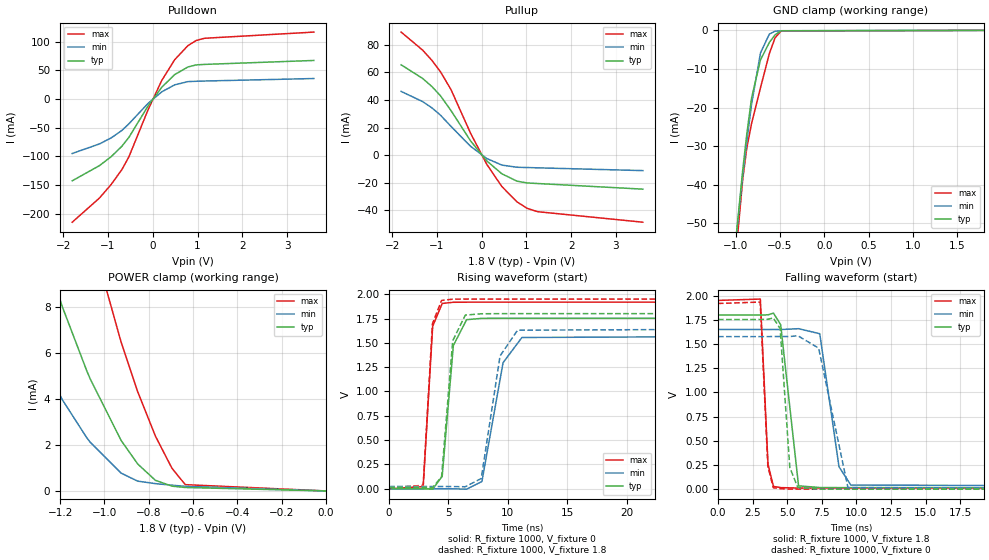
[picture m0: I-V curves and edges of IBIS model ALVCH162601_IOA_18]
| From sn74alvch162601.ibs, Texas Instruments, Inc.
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[Model]   ALVCH162601_IOA_18
Model_type  I/O
Vinl=0.5775
Vinh=1.2675
Enable   Active-Low
Vref =   0
Rref =   1000
Cref =   30p
Vmeas =   0.9
| variable   typ   min   max
C_comp   8.60pF   7.58pF   9.42pF
| C_pullup   9.70pF   8.14pF   10.52pF
| C_pulldown   13.30pF   10.04pF   17.23pF
| C_tri-state   8.60pF   7.58pF   9.42pF
[Temperature Range]   40   100   -40
| Ambient temperature   25   85   -40
[Voltage range]   1.8   1.65   1.95
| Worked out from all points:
|   slope of the pulldown table from 0 to 0.27 V, typ, clamps not added: 10.2 ohm
|   slope of the pullup table from 0 to 0.27 V, typ, clamps not added: 30.2 ohm
|   GND clamp passes 1 mA (typ) near -0.55 V on its own axis
|   POWER clamp passes 1 mA (typ) near -0.83 V on its own axis
|   rising waveform, R_fixture 1000, V_fixture 0: 20-80 % time 655ps typ, 1.3ns min, 392ps max; typ from 0 V to 1.75 V
|   falling waveform, R_fixture 1000, V_fixture 1.8: 20-80 % time 461ps typ, 839ps min, 271ps max; typ from 1.8 V to 0.016 V
|   rising waveform, R_fixture 1000, V_fixture 1.8: 20-80 % time 620ps typ, 1.14ns min, 383ps max; typ from 0.016 V to 1.8 V
|   falling waveform, R_fixture 1000, V_fixture 0: 20-80 % time 453ps typ, 852ps min, 267ps max; typ from 1.75 V to 0 V
[GND Clamp]
| ALVCH162601_IOA_18
|   Voltage   I(typ)   I(min)   I(max)
-1.8V     -267.7mA   -247.3mA   -300.9mA
-1.09V    -76.1mA    -74.2mA    -82.32mA
-1.075V   -72.37mA   -70.82mA   -78.1mA
-1.055V   -67.46mA   -66.36mA   -72.53mA
-920mV    -36.17mA   -37.65mA   -38.59mA
-875mV    -26.98mA   -28.88mA   -30.56mA
-820mV    -17.47mA   -19.08mA   -24.08mA
-720mV    -7.652mA   -5.864mA   -14.89mA
-620mV    -3.141mA   -959.9uA   -6.029mA
-555mV    -1.142mA   -210.2uA   -1.921mA
-485mV    -97.9uA    -108.2uA   -133.2uA
1.8V      63.53pA    9.524uA    -22.72uA
[POWER Clamp]
| ALVCH162601_IOA_18
|   Voltage   I(typ)   I(min)   I(max)
-1.8V     29.94mA    18.79mA    48.32mA
-1.545V   19.69mA    11.65mA    33.78mA
-1.31V    11.56mA    6.211mA    21.83mA
-1.19V    8.026mA    3.974mA    16.4mA
-1.08V    5.242mA    2.322mA    11.91mA
-1.065V   4.9mA      2.13mA     11.33mA
-925mV    2.204mA    777.7uA    6.495mA
-850mV    1.177mA    426.3uA    4.328mA
-770mV    462.3uA    318uA      2.392mA
-695mV    208uA      249.8uA    983.5uA
-635mV    150uA      199.3uA    273.7uA
-16.28fV  63.53pA    285.3pA    36.64pA
[Pulldown]
| ALVCH162601_IOA_18
|   Voltage   I(typ)   I(min)   I(max)
-1.8V     -142.5mA   -94.94mA   -214.6mA
-1.19V    -116mA     -78.24mA   -172.4mA
-930mV    -100.5mA   -67.79mA   -148.9mA
-690mV    -82.3mA    -54.81mA   -122.9mA
-535mV    -66.97mA   -43.32mA   -101mA
-105mV    -12.13mA   -7.634mA   -18.73mA
200mV     20.41mA    12.38mA    32.16mA
490mV     42.45mA    24.65mA    68.46mA
785mV     55.72mA    30.25mA    92.88mA
970mV     59.35mA    30.84mA    101.8mA
1.155V    60.2mA     31.26mA    105.7mA
3.6V      67.09mA    35.62mA    116.5mA
[Pullup]
| ALVCH162601_IOA_18
|   Voltage   I(typ)   I(min)   I(max)
-1.8V     65.54mA    46.25mA    89.25mA
-1.32V    55.67mA    38.89mA    76.19mA
-1.11V    49.72mA    34.29mA    68.65mA
-920mV    43.05mA    29.01mA    60.43mA
-685mV    32.34mA    20.89mA    47.55mA
-250mV    10.47mA    6.526mA    16.03mA
115mV     -4.131mA   -2.38mA    -6.642mA
450mV     -13.44mA   -7.131mA   -22.64mA
790mV     -18.81mA   -8.709mA   -33.84mA
1.02V     -20.1mA    -8.918mA   -38.54mA
1.25V     -20.5mA    -9.124mA   -40.92mA
3.6V      -24.58mA   -11.14mA   -48.53mA
[Ramp]
| ALVCH162601_IOA_18
| variable   typ   min   max
dV/dt_r   1.06/6.61E-10   0.95/1.30E-09   1.15/4.03E-10
dV/dt_f   1.09/4.74E-10   0.99/8.64E-10   1.18/2.83E-10
R_load = 1000
[Rising Waveform]
| ALVCH162601_IOA_18
R_fixture =   1000
C_fixture =   0
L_fixture =   0
V_fixture =   0
V_fixture_min = 0
V_fixture_max = 0
|   Time   V(typ)   V(min)   V(max)
0s        343.1pV    1.757nV    237.2pV
2.875ns   -242.4uV   791uV      22.24mV
3.675ns   -4.049mV   -77.59uV   1.671V
4.475ns   128.7mV    71.71uV    1.905V
5.415ns   1.473V     -263.8uV   1.917V
6.53ns    1.738V     -4.146mV   1.918V
7.82ns    1.752V     75.03mV    1.918V
9.6ns     1.753V     1.296V     1.918V
11.19ns   1.753V     1.555V     1.918V
50ns      1.753V     1.576V     1.918V
[Falling Waveform]
| ALVCH162601_IOA_18
R_fixture =   1000
C_fixture =   0
L_fixture =   0
V_fixture =   1.8
V_fixture_min = 1.65
V_fixture_max = 1.95
|   Time   V(typ)   V(min)   V(max)
0s        1.8V       1.65V      1.95V
3.06ns    1.799V     1.65V      1.964V
3.615ns   1.801V     1.649V     255.6mV
4.01ns    1.819V     1.65V      27.9mV
4.53ns    1.698V     1.649V     16.02mV
5.82ns    34.47mV    1.658V     11.35mV
7.35ns    16.81mV    1.606V     11.09mV
8.74ns    16mV       231.4mV    11.08mV
9.595ns   15.94mV    42.66mV    11.07mV
50ns      15.9mV     23.5mV     11.07mV
[Rising Waveform]
| ALVCH162601_IOA_18
R_fixture =   1000
C_fixture =   0
L_fixture =   0
V_fixture =   1.8
V_fixture_min = 1.65
V_fixture_max = 1.95
|   Time   V(typ)   V(min)   V(max)
0s        15.9mV     23.5mV     11.07mV
2.875ns   15.17mV    24.03mV    35.4mV
3.655ns   12.2mV     22.71mV    1.697V
4.42ns    121.1mV    22.9mV     1.936V
5.36ns    1.521V     22.53mV    1.949V
6.42ns    1.785V     20.58mV    1.95V
7.76ns    1.799V     105.5mV    1.95V
9.345ns   1.8V       1.365V     1.95V
10.82ns   1.8V       1.63V      1.95V
50ns      1.8V       1.65V      1.95V
[Falling Waveform]
| ALVCH162601_IOA_18
R_fixture =   1000
C_fixture =   0
L_fixture =   0
V_fixture =   0
V_fixture_min = 0
V_fixture_max = 0
|   Time   V(typ)   V(min)   V(max)
0s        1.753V     1.576V     1.918V
3.05ns    1.753V     1.576V     1.933V
3.605ns   1.755V     1.576V     231.7mV
4ns       1.769V     1.577V     14.85mV
4.49ns    1.658V     1.577V     4.722mV
5.19ns    222.5mV    1.577V     805.4uV
5.77ns    16.05mV    1.585V     250.2uV
7.27ns    688.2uV    1.457V     20.34uV
9.385ns   27.85uV    16.22mV    2.112uV
50ns      349.7nV    713.3nV    155.7nV
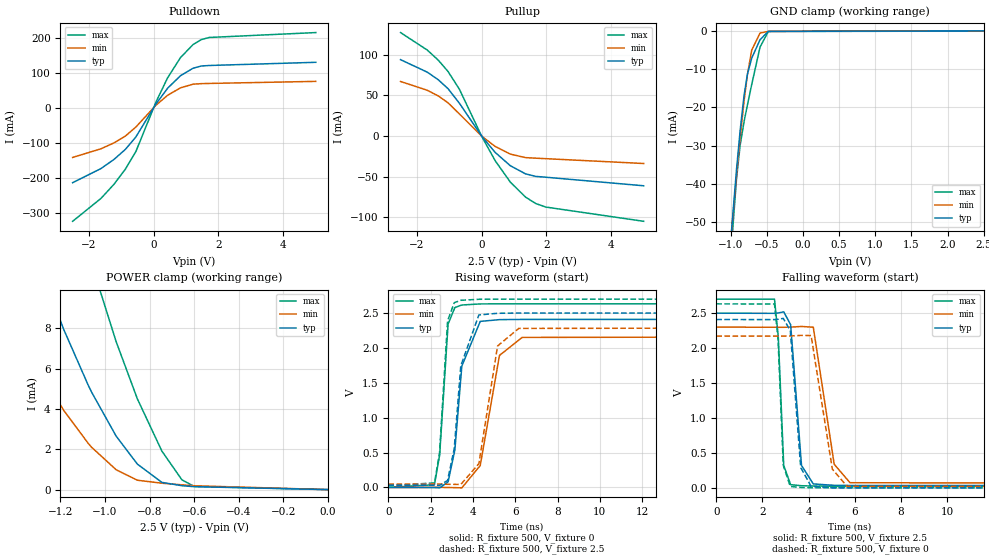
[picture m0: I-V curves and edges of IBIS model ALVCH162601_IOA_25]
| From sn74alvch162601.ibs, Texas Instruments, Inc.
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[Model]   ALVCH162601_IOA_25
Model_type  I/O
Vinl=0.7
Vinh=1.7
Enable   Active-Low
Vref =   0
Rref =   500
Cref =   30p
Vmeas =   1.25
| variable   typ   min   max
C_comp   8.35pF   7.20pF   9.38pF
| C_pullup   9.52pF   7.79pF   10.41pF
| C_pulldown   12.85pF   9.77pF   16.66pF
| C_tri-state   8.35pF   7.20pF   9.38pF
[Temperature Range]   40   100   -40
| Ambient temperature   25   85   -40
[Voltage range]   2.5   2.3   2.7
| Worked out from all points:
|   slope of the pulldown table from 0 to 0.375 V, typ, clamps not added: 7.66 ohm
|   slope of the pullup table from 0 to 0.375 V, typ, clamps not added: 20.6 ohm
|   GND clamp passes 1 mA (typ) near -0.55 V on its own axis
|   POWER clamp passes 1 mA (typ) near -0.83 V on its own axis
|   rising waveform, R_fixture 500, V_fixture 0: 20-80 % time 434ps typ, 661ps min, 293ps max; typ from 0 V to 2.41 V
|   falling waveform, R_fixture 500, V_fixture 2.5: 20-80 % time 287ps typ, 466ps min, 186ps max; typ from 2.5 V to 0.034 V
|   rising waveform, R_fixture 500, V_fixture 2.5: 20-80 % time 418ps typ, 607ps min, 286ps max; typ from 0.034 V to 2.5 V
|   falling waveform, R_fixture 500, V_fixture 0: 20-80 % time 276ps typ, 437ps min, 181ps max; typ from 2.41 V to 0 V
[GND Clamp]
| ALVCH162601_IOA_25
|   Voltage   I(typ)   I(min)   I(max)
-2.5V     -468.2mA   -428.5mA   -529.7mA
-1.095V   -77.4mA    -75.37mA   -83.81mA
-1.08V    -73.67mA   -71.99mA   -79.57mA
-1.06V    -68.73mA   -67.51mA   -73.98mA
-920mV    -36.21mA   -37.68mA   -38.65mA
-870mV    -26.07mA   -27.97mA   -29.9mA
-815mV    -16.78mA   -18.28mA   -23.65mA
-770mV    -11.4mA    -11.53mA   -19.45mA
-710mV    -7.125mA   -5.047mA   -14.04mA
-595mV    -2.318mA   -568.8uA   -4.241mA
-480mV    -118.2uA   -124.4uA   -159.8uA
2.5V      87.96pA    20.8uA     -42.68uA
[POWER Clamp]
| ALVCH162601_IOA_25
|   Voltage   I(typ)   I(min)   I(max)
-2.5V     63.25mA    42.74mA    94.06mA
-1.535V   19.36mA    11.44mA    33.3mA
-1.295V   11.13mA    5.943mA    21.18mA
-1.185V   7.93mA     3.923mA    16.24mA
-1.075V   5.165mA    2.287mA    11.76mA
-1.06V    4.826mA    2.097mA    11.19mA
-950mV    2.649mA    983.8uA    7.329mA
-855mV    1.266mA    465.9uA    4.501mA
-745mV    358.2uA    317uA      1.91mA
-655mV    193uA      236.3uA    483.8uA
-600mV    145.9uA    190.2uA    159.3uA
-31.15fV  87.96pA    322.3pA    50.89pA
[Pulldown]
| ALVCH162601_IOA_25
|   Voltage   I(typ)   I(min)   I(max)
-2.5V     -214.5mA   -142.4mA   -324.7mA
-1.625V   -174.1mA   -117.7mA   -259.4mA
-1.225V   -148.2mA   -100.9mA   -219.1mA
-870mV    -119.2mA   -81.23mA   -175.5mA
-550mV    -84.06mA   -55.7mA    -125.8mA
75mV      10.83mA    7.022mA    16.48mA
430mV     55.09mA    35.04mA    84.84mA
825mV     90.83mA    56.18mA    142.3mA
1.215V    112.2mA    66.71mA    179.9mA
1.465V    118.6mA    68.28mA    193.9mA
1.715V    120.1mA    68.86mA    200.1mA
5V        129.2mA    74.77mA    214.1mA
[Pullup]
| ALVCH162601_IOA_25
|   Voltage   I(typ)   I(min)   I(max)
-2.5V     93.89mA    67.09mA    127.2mA
-1.675V   78.56mA    56.27mA    105.7mA
-1.335V   69.15mA    49.28mA    93.27mA
-1.035V   58.23mA    40.89mA    79.35mA
-685mV    40.38mA    27.22mA    57.59mA
15mV      -812.9uA   -531.7uA   -1.2mA
420mV     -20.15mA   -12.8mA    -30.36mA
885mV     -36.42mA   -22.17mA   -56.52mA
1.355V    -46.47mA   -26.53mA   -75.01mA
1.67V     -49.6mA    -27.19mA   -82.95mA
1.985V    -50.63mA   -27.82mA   -87.32mA
5V        -61.14mA   -33.76mA   -104.8mA
[Ramp]
| ALVCH162601_IOA_25
| variable   typ   min   max
dV/dt_r   1.45/4.39E-10   1.31/6.69E-10   1.58/3.02E-10
dV/dt_f   1.49/2.97E-10   1.37/4.76E-10   1.61/1.96E-10
R_load = 500
[Rising Waveform]
| ALVCH162601_IOA_25
R_fixture =   500
C_fixture =   0
L_fixture =   0
V_fixture =   0
V_fixture_min = 0
V_fixture_max = 0
|   Time   V(typ)   V(min)   V(max)
0s        360.6pV    1.412nV    255.5pV
2.18ns    -1.225mV   1.259mV    39.19mV
2.425ns   -5.484mV   1.303mV    463.5mV
2.825ns   79.71mV    -1.195mV   2.343V
3.145ns   537.1mV    -2.771mV   2.579V
3.475ns   1.74V      -6.033mV   2.616V
4.345ns   2.381V     314.4mV    2.631V
5.255ns   2.406V     1.893V     2.633V
6.325ns   2.409V     2.151V     2.633V
50ns      2.409V     2.172V     2.633V
[Falling Waveform]
| ALVCH162601_IOA_25
R_fixture =   500
C_fixture =   0
L_fixture =   0
V_fixture =   2.5
V_fixture_min = 2.3
V_fixture_max = 2.7
|   Time   V(typ)   V(min)   V(max)
0s        2.5V       2.3V       2.7V
2.52ns    2.498V     2.299V     2.701V
2.685ns   2.503V     2.298V     2.159V
2.92ns    2.519V     2.298V     320.8mV
3.22ns    2.334V     2.3V       45.51mV
3.69ns    321.2mV    2.31V      30.65mV
4.2ns     56.19mV    2.299V     25.72mV
5.105ns   36.28mV    338.1mV    24.25mV
5.79ns    34.36mV    73.6mV     24.04mV
50ns      33.66mV    47.56mV    23.96mV
[Rising Waveform]
| ALVCH162601_IOA_25
R_fixture =   500
C_fixture =   0
L_fixture =   0
V_fixture =   2.5
V_fixture_min = 2.3
V_fixture_max = 2.7
|   Time   V(typ)   V(min)   V(max)
0s        33.65mV    47.56mV    23.96mV
2.18ns    31.61mV    48.56mV    65.4mV
2.42ns    28.2mV     47.98mV    493.7mV
2.8ns     100.2mV    45.23mV    2.387V
3.115ns   555.8mV    44.17mV    2.649V
3.425ns   1.743V     42.8mV     2.683V
4.28ns    2.473V     340.7mV    2.698V
5.165ns   2.497V     2.028V     2.7V
6.165ns   2.5V       2.28V      2.7V
50ns      2.5V       2.3V       2.7V
[Falling Waveform]
| ALVCH162601_IOA_25
R_fixture =   500
C_fixture =   0
L_fixture =   0
V_fixture =   0
V_fixture_min = 0
V_fixture_max = 0
|   Time   V(typ)   V(min)   V(max)
0s        2.409V     2.172V     2.633V
2.52ns    2.408V     2.172V     2.631V
2.675ns   2.413V     2.171V     2.122V
2.9ns     2.425V     2.172V     322.6mV
3.205ns   2.25V      2.174V     19.25mV
3.655ns   291mV      2.182V     6.186mV
4.105ns   21.28mV    2.18V      1.775mV
5.025ns   2.208mV    268.6mV    270.6uV
5.66ns    597.8uV    21.81mV    82.62uV
50ns      230.4nV    435.9nV    113.9nV
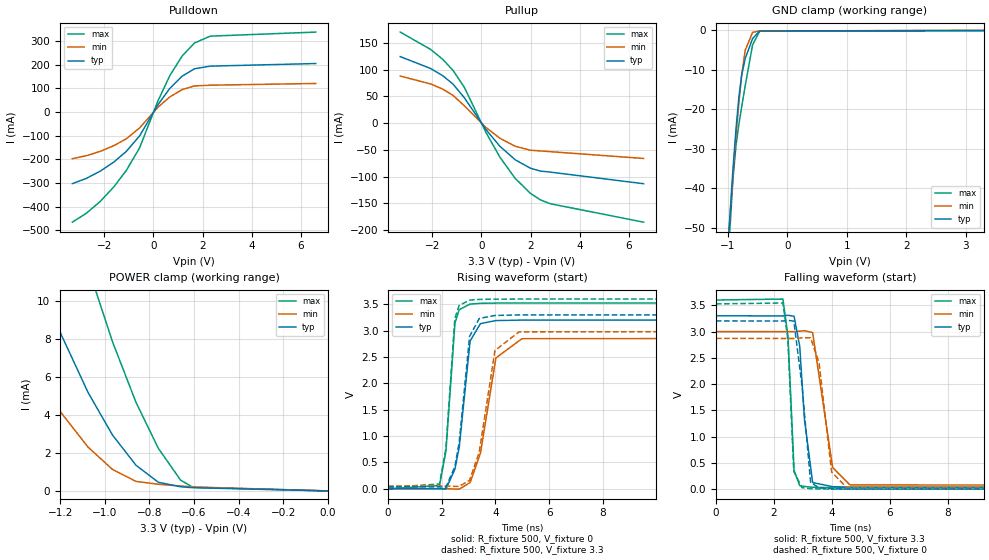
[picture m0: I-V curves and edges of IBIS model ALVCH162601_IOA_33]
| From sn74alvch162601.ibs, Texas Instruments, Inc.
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[Model]   ALVCH162601_IOA_33
Model_type  I/O
Vinl=0.8
Vinh=2.0
Enable   Active-Low
Vref =   0
Rref =   500
Cref =   50p
Vmeas =   1.5
| variable   typ   min   max
C_comp   8.14pF   6.92pF   9.36pF
| C_pullup   9.28pF   7.54pF   10.22pF
| C_pulldown   12.48pF   9.71pF   15.98pF
| C_tri-state   8.14pF   6.92pF   9.36pF
[Temperature Range]   40   100   -40
| Ambient temperature   25   85   -40
[Voltage range]   3.3   3   3.6
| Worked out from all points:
|   slope of the pulldown table from 0 to 0.495 V, typ, clamps not added: 6.36 ohm
|   slope of the pullup table from 0 to 0.495 V, typ, clamps not added: 16.5 ohm
|   GND clamp passes 1 mA (typ) near -0.55 V on its own axis
|   POWER clamp passes 1 mA (typ) near -0.83 V on its own axis
|   rising waveform, R_fixture 500, V_fixture 0: 20-80 % time 366ps typ, 516ps min, 262ps max; typ from 0 V to 3.2 V
|   falling waveform, R_fixture 500, V_fixture 3.3: 20-80 % time 228ps typ, 339ps min, 157ps max; typ from 3.3 V to 0.037 V
|   rising waveform, R_fixture 500, V_fixture 3.3: 20-80 % time 359ps typ, 496ps min, 259ps max; typ from 0.037 V to 3.3 V
|   falling waveform, R_fixture 500, V_fixture 0: 20-80 % time 221ps typ, 323ps min, 154ps max; typ from 3.2 V to 0 V
[GND Clamp]
| ALVCH162601_IOA_33
|   Voltage   I(typ)   I(min)   I(max)
-3.3V     -702.5mA   -640.1mA   -797.1mA
-1.09V    -76.2mA    -74.27mA   -82.45mA
-1.07V    -71.24mA   -69.78mA   -76.83mA
-1.05V    -66.34mA   -65.33mA   -71.28mA
-915mV    -35.19mA   -36.71mA   -37.68mA
-865mV    -25.17mA   -27.07mA   -29.27mA
-815mV    -16.82mA   -18.31mA   -23.7mA
-770mV    -11.44mA   -11.56mA   -19.5mA
-710mV    -7.159mA   -5.072mA   -14.09mA
-585mV    -2.033mA   -471.5uA   -3.632mA
-465mV    -132uA     -129.7uA   -181.2uA
3.3V      119.8pA    41.6uA     -79.23uA
[POWER Clamp]
| ALVCH162601_IOA_33
|   Voltage   I(typ)   I(min)   I(max)
-3.3V     106.7mA    74.61mA    152.6mA
-1.545V   19.78mA    11.73mA    33.9mA
-1.42V    15.27mA    8.669mA    27.34mA
-1.32V    11.95mA    6.481mA    22.41mA
-1.195V   8.24mA     4.119mA    16.72mA
-1.075V   5.198mA    2.312mA    11.8mA
-965mV    2.942mA    1.129mA    7.86mA
-860mV    1.354mA    503uA      4.672mA
-760mV    457.3uA    350.6uA    2.248mA
-660mV    219.9uA    257.6uA    567.3uA
-605mV    170.3uA    210.1uA    193.1uA
-48.03fV  119.8pA    365.6pA    68.2pA
[Pulldown]
| ALVCH162601_IOA_33
|   Voltage   I(typ)   I(min)   I(max)
-3.3V     -302.4mA   -196.9mA   -465.1mA
-2.73V    -280.1mA   -184.3mA   -427.4mA
-2.16V    -249.3mA   -165.8mA   -377mA
-1.61V    -210.9mA   -141.8mA   -315.8mA
-1.105V   -166.3mA   -112.9mA   -246.6mA
-565mV    -100.8mA   -67.07mA   -151.3mA
185mV     31.43mA    20.51mA    47.78mA
665mV     100mA      64.12mA    153.8mA
1.17V     151.9mA    95.01mA    237.4mA
1.67V     182.8mA    110.5mA    291.9mA
2.31V     194mA      113.5mA    320.7mA
6.6V      205mA      120.8mA    337.8mA
[Pullup]
| ALVCH162601_IOA_33
|   Voltage   I(typ)   I(min)   I(max)
-3.3V     124.6mA    88.26mA    170.5mA
-2.055V   102.2mA    73.29mA    137.8mA
-1.565V   88.69mA    63.61mA    119.2mA
-1.15V    73.01mA    51.93mA    98.57mA
-690mV    47.45mA    32.47mA    66.81mA
180mV     -11.59mA   -7.766mA   -16.76mA
755mV     -43.3mA    -28.29mA   -63.76mA
1.375V    -68.47mA   -43.2mA    -103.3mA
1.995V    -84.31mA   -50.62mA   -131.4mA
2.405V    -89.66mA   -51.96mA   -143.6mA
2.81V     -91.58mA   -53.32mA   -150.8mA
6.6V      -113.3mA   -66.05mA   -185.3mA
[Ramp]
| ALVCH162601_IOA_33
| variable   typ   min   max
dV/dt_r   1.93/3.76E-10   1.73/5.26E-10   2.12/2.63E-10
dV/dt_f   1.97/2.33E-10   1.78/3.47E-10   2.16/1.62E-10
R_load = 500
[Rising Waveform]
| ALVCH162601_IOA_33
R_fixture =   500
C_fixture =   0
L_fixture =   0
V_fixture =   0
V_fixture_min = 0
V_fixture_max = 0
|   Time   V(typ)   V(min)   V(max)
0s        395.9pV    1.295nV    284.2pV
1.915ns   -1.436mV   1.532mV    60.45mV
2.155ns   -5.386mV   1.587mV    716mV
2.49ns    371.6mV    -5.607mV   3.146V
2.65ns    791.4mV    -8.056mV   3.399V
3.055ns   2.804V     117.9mV    3.505V
3.44ns    3.134V     674.8mV    3.519V
4.015ns   3.192V     2.482V     3.524V
4.985ns   3.201V     2.848V     3.526V
50ns      3.202V     2.869V     3.526V
[Falling Waveform]
| ALVCH162601_IOA_33
R_fixture =   500
C_fixture =   0
L_fixture =   0
V_fixture =   3.3
V_fixture_min = 3
V_fixture_max = 3.6
|   Time   V(typ)   V(min)   V(max)
0s        3.3V       3V         3.6V
2.31ns    3.297V     2.999V     3.618V
2.485ns   3.31V      2.998V     2.904V
2.695ns   3.29V      2.998V     358.1mV
2.89ns    2.717V     3.007V     67.21mV
3.05ns    1.344V     3.016V     51.25mV
3.335ns   126.2mV    2.98V      35.94mV
4.025ns   47.06mV    411.8mV    28.2mV
4.62ns    39.16mV    81.7mV     27.13mV
50ns      37.01mV    51.2mV     26.69mV
[Rising Waveform]
| ALVCH162601_IOA_33
R_fixture =   500
C_fixture =   0
L_fixture =   0
V_fixture =   3.3
V_fixture_min = 3
V_fixture_max = 3.6
|   Time   V(typ)   V(min)   V(max)
0s        37.01mV    51.2mV     26.69mV
1.915ns   34.91mV    52.52mV    89.01mV
2.155ns   32.26mV    51.84mV    771.3mV
2.485ns   414.7mV    45.03mV    3.226V
2.645ns   867.6mV    43.64mV    3.478V
3.035ns   2.892V     160.6mV    3.58V
3.395ns   3.231V     696.1mV    3.593V
3.98ns    3.289V     2.624V     3.598V
4.88ns    3.299V     2.978V     3.6V
50ns      3.3V       3V         3.6V
[Falling Waveform]
| ALVCH162601_IOA_33
R_fixture =   500
C_fixture =   0
L_fixture =   0
V_fixture =   0
V_fixture_min = 0
V_fixture_max = 0
|   Time   V(typ)   V(min)   V(max)
0s        3.202V     2.869V     3.526V
2.31ns    3.2V       2.868V     3.543V
2.48ns    3.213V     2.867V     2.85V
2.685ns   3.198V     2.868V     337.4mV
2.97ns    1.966V     2.881V     27.34mV
3.265ns   130.8mV    2.881V     10.39mV
3.56ns    24.91mV    2.395V     3.831mV
3.99ns    8.969mV    327.2mV    1.392mV
4.515ns   2.122mV    28.77mV    464.4uV
50ns      174.6nV    320.4nV    86.24nV
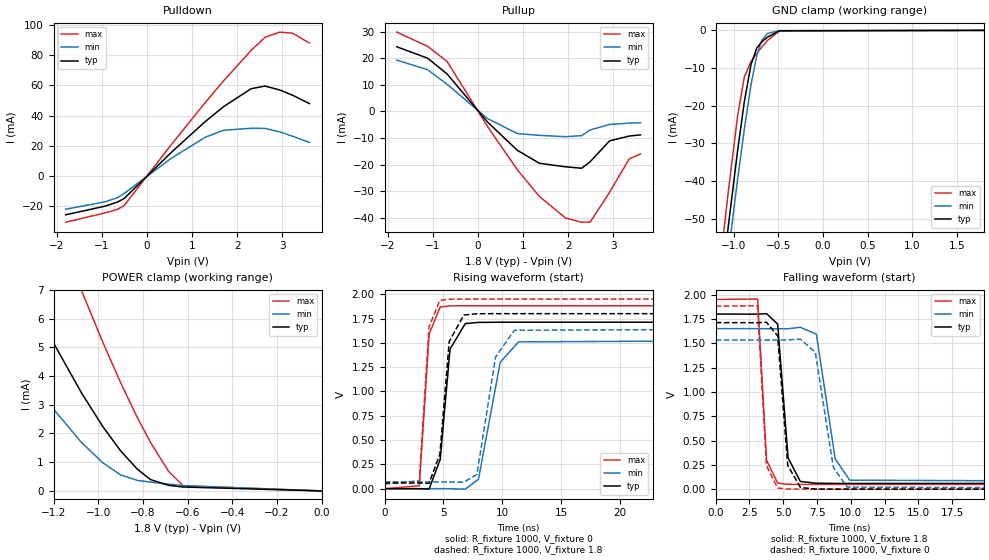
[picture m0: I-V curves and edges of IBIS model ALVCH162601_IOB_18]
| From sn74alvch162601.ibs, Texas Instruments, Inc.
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[Model]   ALVCH162601_IOB_18
Model_type  I/O
Vinl=0.5775
Vinh=1.2675
Enable   Active-Low
Vref =   0
Rref =   1000
Cref =   30p
Vmeas =   0.9
| variable   typ   min   max
C_comp   8.46pF   7.17pF   9.31pF
| C_pullup   7.53pF   5.49pF   9.61pF
| C_pulldown   7.53pF   5.49pF   9.61pF
| C_tri-state   8.46pF   7.17pF   9.31pF
[Temperature Range]   40   100   -40
| Ambient temperature   25   85   -40
[Voltage range]   1.8   1.65   1.95
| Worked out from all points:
|   slope of the pulldown table from 0 to 0.27 V, typ, clamps not added: 34.2 ohm
|   slope of the pullup table from 0 to 0.27 V, typ, clamps not added: 53.3 ohm
|   GND clamp passes 1 mA (typ) near -0.57 V on its own axis
|   POWER clamp passes 1 mA (typ) near -0.86 V on its own axis
|   rising waveform, R_fixture 1000, V_fixture 0: 20-80 % time 716ps typ, 1.32ns min, 466ps max; typ from 0 V to 1.71 V
|   falling waveform, R_fixture 1000, V_fixture 1.8: 20-80 % time 529ps typ, 893ps min, 346ps max; typ from 1.8 V to 0.059 V
|   rising waveform, R_fixture 1000, V_fixture 1.8: 20-80 % time 683ps typ, 1.17ns min, 458ps max; typ from 0.059 V to 1.8 V
|   falling waveform, R_fixture 1000, V_fixture 0: 20-80 % time 521ps typ, 908ps min, 343ps max; typ from 1.71 V to 0 V
[GND Clamp]
| ALVCH162601_IOB_18
|   Voltage   I(typ)   I(min)   I(max)
-1.8V     -210.5mA   -213.3mA   -208.1mA
-1.145V   -69.35mA   -76.29mA   -60.75mA
-1.105V   -61.16mA   -68.31mA   -52.23mA
-1.06V    -52.1mA    -59.46mA   -42.85mA
-955mV    -31.87mA   -39.5mA    -22.66mA
-880mV    -18.94mA   -26.2mA    -12.37mA
-805mV    -9.029mA   -14.43mA   -8.258mA
-740mV    -4.65mA    -6.61mA    -6.135mA
-685mV    -3.043mA   -2.694mA   -4.475mA
-620mV    -1.783mA   -796.2uA   -2.665mA
-485mV    -96.67uA   -107.2uA   -131.7uA
1.8V      63.53pA    9.524uA    -22.72uA
[POWER Clamp]
| ALVCH162601_IOB_18
|   Voltage   I(typ)   I(min)   I(max)
-1.8V     15.34mA    10.39mA    23.37mA
-1.545V   10.74mA    6.906mA    17.22mA
-1.32V    6.986mA    4.147mA    12.09mA
-1.195V   5.081mA    2.802mA    9.414mA
-1.075V   3.416mA    1.69mA     6.984mA
-980mV    2.247mA    984.2uA    5.185mA
-900mV    1.399mA    559.2uA    3.774mA
-825mV    758.5uA    366.9uA    2.558mA
-765mV    392.7uA    307.1uA    1.677mA
-685mV    194.7uA    237.1uA    681.5uA
-620mV    136.7uA    184.3uA    179.7uA
-16.28fV  63.53pA    285.3pA    36.64pA
[Pulldown]
| ALVCH162601_IOB_18
|   Voltage   I(typ)   I(min)   I(max)
-1.8V     -25.65mA   -21.98mA   -30.53mA
-920mV    -19.87mA   -17.01mA   -24.33mA
-655mV    -17.23mA   -14.32mA   -22.12mA
-505mV    -14.88mA   -11.53mA   -19.53mA
550mV     15.9mA     11.93mA    21.11mA
1.29V     35.91mA    25.58mA    48.49mA
1.695V    45.8mA     30.26mA    62.78mA
2.31V     57.72mA    31.54mA    83.02mA
2.615V    59.47mA    31.49mA    91.67mA
2.945V    56.88mA    29.16mA    95.15mA
3.23V     53.37mA    26.28mA    94.4mA
3.6V      47.9mA     22.21mA    87.95mA
[Pullup]
| ALVCH162601_IOB_18
|   Voltage   I(typ)   I(min)   I(max)
-1.8V     24.29mA    19.27mA    29.81mA
-1.115V   19.98mA    15.66mA    24.43mA
-685mV    14.08mA    10.2mA     18.77mA
210mV     -3.976mA   -2.661mA   -5.642mA
870mV     -14.59mA   -8.321mA   -21.89mA
1.36V     -19.48mA   -8.981mA   -31.95mA
1.94V     -20.8mA    -9.48mA    -40.05mA
2.295V    -21.34mA   -9.103mA   -41.61mA
2.485V    -18.89mA   -6.958mA   -41.58mA
2.915V    -11.06mA   -4.89mA    -30.39mA
3.35V     -9.248mA   -4.39mA    -17.84mA
3.6V      -8.807mA   -4.241mA   -15.97mA
[Ramp]
| ALVCH162601_IOB_18
| variable   typ   min   max
dV/dt_r   1.03/7.20E-10   0.92/1.32E-09   1.13/4.72E-10
dV/dt_f   1.06/5.40E-10   0.97/9.13E-10   1.15/3.58E-10
R_load = 1000
[Rising Waveform]
| ALVCH162601_IOB_18
R_fixture =   1000
C_fixture =   0
L_fixture =   0
V_fixture =   0
V_fixture_min = 0
V_fixture_max = 0
|   Time   V(typ)   V(min)   V(max)
0s        407pV      1.839nV    289.8pV
2.95ns    -80.44uV   606.5uV    30.23mV
3.785ns   -3.742mV   -2.296uV   1.59V
4.73ns    302.6mV    83.19uV    1.869V
5.565ns   1.436V     -317.3uV   1.88V
6.86ns    1.698V     -4.718mV   1.881V
7.985ns   1.71V      97.82mV    1.881V
9.835ns   1.712V     1.301V     1.881V
11.4ns    1.712V     1.51V      1.881V
50ns      1.712V     1.533V     1.881V
[Falling Waveform]
| ALVCH162601_IOB_18
R_fixture =   1000
C_fixture =   0
L_fixture =   0
V_fixture =   1.8
V_fixture_min = 1.65
V_fixture_max = 1.95
|   Time   V(typ)   V(min)   V(max)
0s        1.8V       1.65V      1.95V
3.1ns     1.799V     1.65V      1.954V
3.765ns   1.804V     1.649V     297.5mV
4.585ns   1.697V     1.649V     62.4mV
5.36ns    320.9mV    1.649V     49.83mV
6.265ns   79.19mV    1.664V     48.93mV
7.455ns   60.78mV    1.593V     48.77mV
8.845ns   59.06mV    312mV      48.74mV
9.925ns   58.96mV    92.39mV    48.73mV
50ns      58.91mV    70.13mV    48.73mV
[Rising Waveform]
| ALVCH162601_IOB_18
R_fixture =   1000
C_fixture =   0
L_fixture =   0
V_fixture =   1.8
V_fixture_min = 1.65
V_fixture_max = 1.95
|   Time   V(typ)   V(min)   V(max)
0s        58.91mV    70.13mV    48.73mV
2.95ns    58.39mV    70.54mV    81.23mV
3.775ns   55.43mV    69.49mV    1.664V
4.7ns     354.5mV    69.58mV    1.938V
5.495ns   1.513V     69.18mV    1.948V
6.735ns   1.786V     67.43mV    1.95V
7.85ns    1.799V     146.7mV    1.95V
9.435ns   1.8V       1.353V     1.95V
11.03ns   1.8V       1.629V     1.95V
50ns      1.8V       1.65V      1.95V
[Falling Waveform]
| ALVCH162601_IOB_18
R_fixture =   1000
C_fixture =   0
L_fixture =   0
V_fixture =   0
V_fixture_min = 0
V_fixture_max = 0
|   Time   V(typ)   V(min)   V(max)
0s        1.712V     1.533V     1.881V
3.09ns    1.711V     1.533V     1.885V
3.755ns   1.716V     1.532V     243.2mV
4.585ns   1.576V     1.533V     12.07mV
5.335ns   243.7mV    1.534V     954.1uV
6.275ns   17.42mV    1.542V     164.2uV
7.375ns   1.464mV    1.407V     36.44uV
8.705ns   122.2uV    226mV      10.68uV
9.73ns    42.19uV    21.3mV     6.362uV
50ns      1.309uV    2.142uV    707.7nV
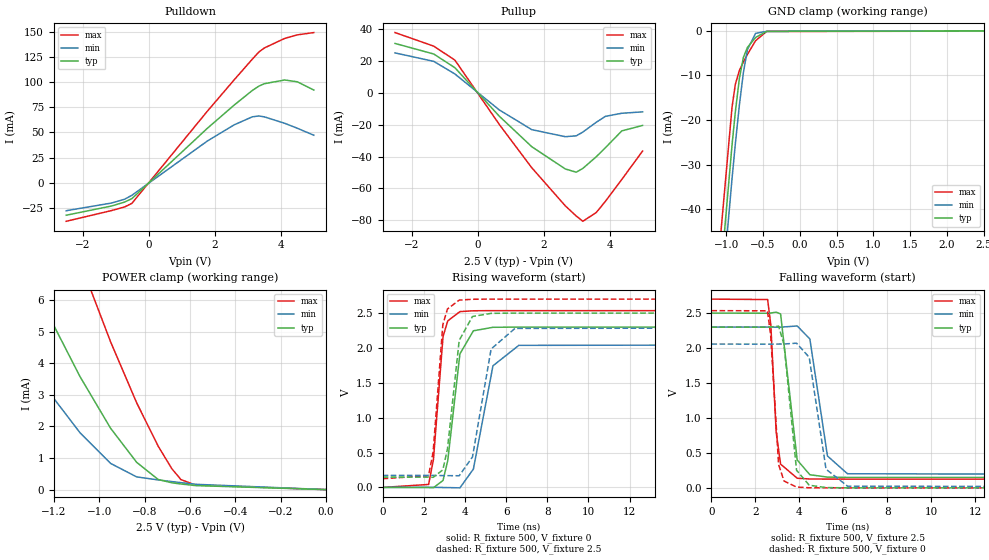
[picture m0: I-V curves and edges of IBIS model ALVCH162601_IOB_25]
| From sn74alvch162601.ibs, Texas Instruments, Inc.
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[Model]   ALVCH162601_IOB_25
Model_type  I/O
Vinl=0.7
Vinh=1.7
Enable   Active-Low
Vref =   0
Rref =   500
Cref =   30p
Vmeas =   1.25
| variable   typ   min   max
C_comp   8.24pF   6.75pF   9.31pF
| C_pullup   6.53pF   4.91pF   9.24pF
| C_pulldown   5.94pF   4.66pF   9.24pF
| C_tri-state   8.24pF   6.75pF   9.31pF
[Temperature Range]   40   100   -40
| Ambient temperature   25   85   -40
[Voltage range]   2.5   2.3   2.7
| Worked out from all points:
|   slope of the pulldown table from 0 to 0.375 V, typ, clamps not added: 32 ohm
|   slope of the pullup table from 0 to 0.375 V, typ, clamps not added: 44.3 ohm
|   GND clamp passes 1 mA (typ) near -0.57 V on its own axis
|   POWER clamp passes 1 mA (typ) near -0.85 V on its own axis
|   rising waveform, R_fixture 500, V_fixture 0: 20-80 % time 505ps typ, 722ps min, 364ps max; typ from 0 V to 2.3 V
|   falling waveform, R_fixture 500, V_fixture 2.5: 20-80 % time 367ps typ, 537ps min, 261ps max; typ from 2.5 V to 0.149 V
|   rising waveform, R_fixture 500, V_fixture 2.5: 20-80 % time 489ps typ, 674ps min, 358ps max; typ from 0.149 V to 2.5 V
|   falling waveform, R_fixture 500, V_fixture 0: 20-80 % time 364ps typ, 518ps min, 261ps max; typ from 2.3 V to 0 V
[GND Clamp]
| ALVCH162601_IOB_25
|   Voltage   I(typ)   I(min)   I(max)
-2.5V     -366.4mA   -364.8mA   -370.3mA
-1.15V    -70.43mA   -77.33mA   -61.89mA
-1.115V   -63.25mA   -70.34mA   -54.41mA
-1.07V    -54.15mA   -61.46mA   -44.98mA
-920mV    -25.65mA   -33.19mA   -17.16mA
-875mV    -18.2mA    -25.39mA   -11.99mA
-820mV    -10.68mA   -16.64mA   -8.87mA
-765mV    -5.913mA   -9.29mA    -6.974mA
-710mV    -3.695mA   -4.173mA   -5.266mA
-600mV    -1.477mA   -551.2uA   -2.198mA
-450mV    -100.1uA   -100.7uA   -139.6uA
2.5V      87.96pA    20.8uA     -42.68uA
[POWER Clamp]
| ALVCH162601_IOB_25
|   Voltage   I(typ)   I(min)   I(max)
-2.5V     29.26mA    21.19mA    41.6mA
-1.575V   11.31mA    7.339mA    17.99mA
-1.33V    7.189mA    4.297mA    12.37mA
-1.205V   5.269mA    2.936mA    9.674mA
-1.085V   3.585mA    1.805mA    7.228mA
-950mV    1.946mA    830.8uA    4.685mA
-835mV    864.4uA    402.7uA    2.751mA
-740mV    319.6uA    307uA      1.374mA
-680mV    215.8uA    254.1uA    662.1uA
-640mV    178uA      220.3uA    318.1uA
-575mV    127.2uA    168uA      143uA
-31.15fV  87.96pA    322.3pA    50.89pA
[Pulldown]
| ALVCH162601_IOB_25
|   Voltage   I(typ)   I(min)   I(max)
-2.5V     -32.43mA   -27.95mA   -38.48mA
-1.125V   -23.26mA   -20.28mA   -27.77mA
-730mV    -19.32mA   -16.51mA   -24.2mA
-510mV    -15.9mA    -12.59mA   -20.61mA
1.78V     54.23mA    41.53mA    71.26mA
2.59V     77.25mA    57.56mA    102.4mA
3.14V     91.8mA     65.55mA    123mA
3.335V    96.06mA    66.38mA    130mA
3.505V    98.5mA     65.47mA    134.1mA
4.12V     102.2mA    59.07mA    143.6mA
4.5V      100.4mA    54.17mA    147.1mA
5V        92.22mA    47.22mA    149.4mA
[Pullup]
| ALVCH162601_IOB_25
|   Voltage   I(typ)   I(min)   I(max)
-2.5V     31.21mA    25.25mA    38.05mA
-1.325V   24.54mA    19.91mA    29.49mA
-685mV    15.91mA    11.97mA    20.69mA
660mV     -14.63mA   -10.67mA   -19.8mA
1.645V    -33.85mA   -23.09mA   -47.11mA
2.66V     -47.85mA   -27.51mA   -71.08mA
2.99V     -49.86mA   -26.98mA   -77.46mA
3.19V     -47.5mA    -24.61mA   -80.79mA
3.595V    -40.18mA   -18.46mA   -75.27mA
3.875V    -34.45mA   -14.7mA    -68.21mA
4.37V     -23.87mA   -12.76mA   -54.45mA
5V        -20.43mA   -11.88mA   -36.56mA
[Ramp]
| ALVCH162601_IOB_25
| variable   typ   min   max
dV/dt_r   1.38/5.15E-10   1.24/7.27E-10   1.52/3.68E-10
dV/dt_f   1.42/3.77E-10   1.29/5.44E-10   1.55/2.70E-10
R_load = 500
[Rising Waveform]
| ALVCH162601_IOB_25
R_fixture =   500
C_fixture =   0
L_fixture =   0
V_fixture =   0
V_fixture_min = 0
V_fixture_max = 0
|   Time   V(typ)   V(min)   V(max)
0s        436.9pV    1.484nV    320.7pV
2.235ns   -676.4uV   843.4uV    42.99mV
2.47ns    -3.905mV   1.049mV    403.8mV
2.935ns   100.6mV    -846.2uV   2.164V
3.165ns   386.1mV    -1.907mV   2.388V
3.755ns   1.915V     -5.954mV   2.521V
4.41ns    2.246V     263.5mV    2.533V
5.36ns    2.296V     1.744V     2.535V
6.615ns   2.299V     2.037V     2.535V
50ns      2.299V     2.057V     2.535V
[Falling Waveform]
| ALVCH162601_IOB_25
R_fixture =   500
C_fixture =   0
L_fixture =   0
V_fixture =   2.5
V_fixture_min = 2.3
V_fixture_max = 2.7
|   Time   V(typ)   V(min)   V(max)
0s        2.5V       2.3V       2.7V
2.555ns   2.498V     2.3V       2.694V
2.7ns     2.501V     2.299V     2.334V
2.945ns   2.514V     2.299V     791.4mV
3.145ns   2.488V     2.299V     339.6mV
3.9ns     398.1mV    2.316V     137.7mV
4.475ns   187.9mV    2.13V      126.9mV
5.275ns   153.8mV    456.1mV    125.7mV
6.185ns   149.6mV    201.9mV    125.5mV
50ns      149mV      172.1mV    125.4mV
[Rising Waveform]
| ALVCH162601_IOB_25
R_fixture =   500
C_fixture =   0
L_fixture =   0
V_fixture =   2.5
V_fixture_min = 2.3
V_fixture_max = 2.7
|   Time   V(typ)   V(min)   V(max)
0s        149mV      172.1mV    125.4mV
2.23ns    147.8mV    172.7mV    167.5mV
2.455ns   145mV      172.6mV    510.1mV
2.925ns   251.6mV    170.2mV    2.333V
3.15ns    551mV      169.4mV    2.559V
3.72ns    2.109V     167.7mV    2.686V
4.365ns   2.451V     436.5mV    2.698V
5.27ns    2.496V     1.985V     2.7V
6.43ns    2.5V       2.28V      2.7V
50ns      2.5V       2.3V       2.7V
[Falling Waveform]
| ALVCH162601_IOB_25
R_fixture =   500
C_fixture =   0
L_fixture =   0
V_fixture =   0
V_fixture_min = 0
V_fixture_max = 0
|   Time   V(typ)   V(min)   V(max)
0s        2.299V     2.057V     2.535V
2.545ns   2.298V     2.056V     2.533V
2.69ns    2.301V     2.056V     2.197V
3.055ns   2.313V     2.057V     332.2mV
3.3ns     2.05V      2.058V     98.09mV
3.87ns    252.3mV    2.07V      11.47mV
4.445ns   38.16mV    1.868V     1.316mV
5.21ns    4.041mV    267mV      300.7uV
6.19ns    399.2uV    23.84mV    69.86uV
50ns      1.055uV    1.599uV    616.7nV
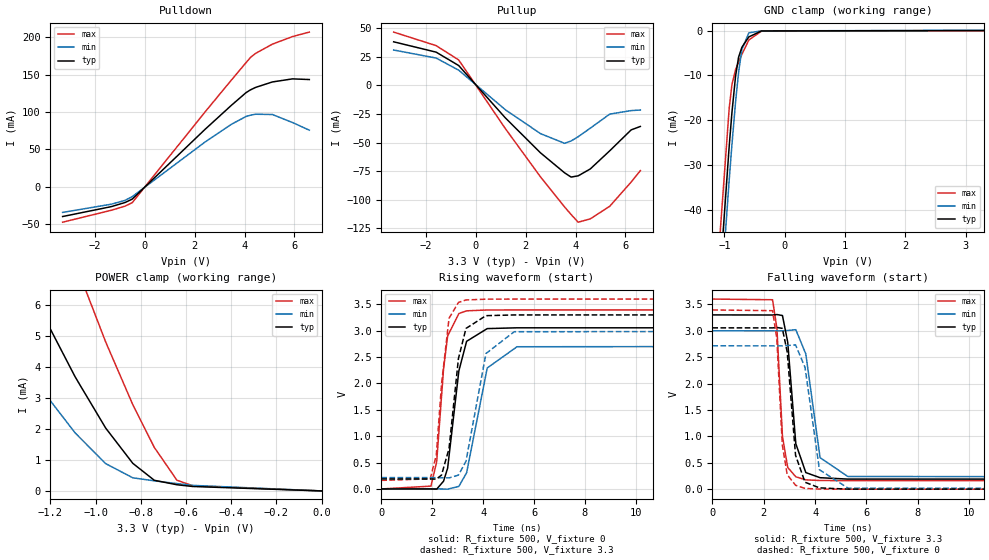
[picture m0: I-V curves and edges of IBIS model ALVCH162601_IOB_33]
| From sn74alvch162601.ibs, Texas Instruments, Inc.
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[Model]   ALVCH162601_IOB_33
Model_type  I/O
Vinl=0.8
Vinh=2.0
Enable   Active-Low
Vref =   0
Rref =   500
Cref =   50p
Vmeas =   1.5
| variable   typ   min   max
C_comp   8.03pF   6.51pF   9.22pF
| C_pullup   5.96pF   4.53pF   8.18pF
| C_pulldown   5.28pF   4.32pF   6.43pF
| C_tri-state   8.03pF   6.51pF   9.22pF
[Temperature Range]   40   100   -40
| Ambient temperature   25   85   -40
[Voltage range]   3.3   3   3.6
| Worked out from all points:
|   slope of the pulldown table from 0 to 0.495 V, typ, clamps not added: 30.8 ohm
|   slope of the pullup table from 0 to 0.495 V, typ, clamps not added: 40.6 ohm
|   GND clamp passes 1 mA (typ) near -0.57 V on its own axis
|   POWER clamp passes 1 mA (typ) near -0.85 V on its own axis
|   rising waveform, R_fixture 500, V_fixture 0: 20-80 % time 436ps typ, 585ps min, 334ps max; typ from 0 V to 3.06 V
|   falling waveform, R_fixture 500, V_fixture 3.3: 20-80 % time 310ps typ, 421ps min, 229ps max; typ from 3.3 V to 0.19 V
|   rising waveform, R_fixture 500, V_fixture 3.3: 20-80 % time 427ps typ, 567ps min, 330ps max; typ from 0.19 V to 3.3 V
|   falling waveform, R_fixture 500, V_fixture 0: 20-80 % time 304ps typ, 416ps min, 230ps max; typ from 3.06 V to 0 V
[GND Clamp]
| ALVCH162601_IOB_33
|   Voltage   I(typ)   I(min)   I(max)
-3.3V     -546.5mA   -540mA     -557.6mA
-1.14V    -68.43mA   -75.37mA   -59.82mA
-1.1V     -60.25mA   -67.4mA    -51.31mA
-1.065V   -53.19mA   -60.52mA   -44.01mA
-920mV    -25.69mA   -33.22mA   -17.22mA
-875mV    -18.25mA   -25.42mA   -12.05mA
-815mV    -10.16mA   -15.93mA   -8.73mA
-765mV    -5.949mA   -9.317mA   -7.024mA
-710mV    -3.729mA   -4.199mA   -5.313mA
-595mV    -1.425mA   -518.9uA   -2.115mA
-385mV    -99.03uA   -79.81uA   -142.6uA
3.3V      119.8pA    41.6uA     -79.23uA
[POWER Clamp]
| ALVCH162601_IOB_33
|   Voltage   I(typ)   I(min)   I(max)
-3.3V     46.44mA    34.69mA    63.82mA
-1.595V   11.71mA    7.639mA    18.52mA
-1.565V   11.18mA    7.241mA    17.81mA
-1.335V   7.309mA    4.385mA    12.53mA
-1.205V   5.306mA    2.964mA    9.721mA
-1.09V    3.685mA    1.874mA    7.37mA
-955mV    2.031mA    882.6uA    4.813mA
-835mV    891.3uA    423.4uA    2.785mA
-740mV    343.9uA    325.8uA    1.406mA
-640mV    199.5uA    236.9uA    346uA
-570mV    143.4uA    179.1uA    166uA
-48.03fV  119.8pA    365.6pA    68.2pA
[Pulldown]
| ALVCH162601_IOB_33
|   Voltage   I(typ)   I(min)   I(max)
-3.3V     -39.7mA    -34.2mA    -47.28mA
-1.35V    -26.49mA   -23.22mA   -31.35mA
-795mV    -20.95mA   -18.12mA   -25.81mA
-510mV    -16.47mA   -13.15mA   -21.24mA
2.405V    76.63mA    59.76mA    99.8mA
3.465V    108.9mA    83.57mA    142.6mA
4.065V    126.2mA    94.28mA    166.4mA
4.245V    129.9mA    95.95mA    173.3mA
4.445V    133.1mA    97.18mA    178.6mA
5.12V     140.4mA    96.81mA    191mA
5.925V    144.5mA    86.08mA    201.1mA
6.6V      143.6mA    75.82mA    207.1mA
[Pullup]
| ALVCH162601_IOB_33
|   Voltage   I(typ)   I(min)   I(max)
-3.3V     37.94mA    30.77mA    46.43mA
-1.595V   28.91mA    23.75mA    34.59mA
-690mV    17.2mA     13.15mA    22.09mA
1.185V    -28.57mA   -21.42mA   -37.96mA
2.59V     -58.98mA   -42.21mA   -79.98mA
3.56V     -76.5mA    -50.72mA   -106.3mA
3.82V     -80.2mA    -48.67mA   -112.9mA
4.105V    -79.11mA   -44.96mA   -119.6mA
4.59V     -73.1mA    -37.49mA   -116.7mA
5.37V     -57.26mA   -25.2mA    -105.7mA
6.23V     -38.98mA   -22.13mA   -84.54mA
6.6V      -35.97mA   -21.63mA   -74.58mA
[Ramp]
| ALVCH162601_IOB_33
| variable   typ   min   max
dV/dt_r   1.84/4.46E-10   1.63/5.94E-10   2.04/3.40E-10
dV/dt_f   1.88/3.12E-10   1.68/4.32E-10   2.07/2.33E-10
R_load = 500
[Rising Waveform]
| ALVCH162601_IOB_33
R_fixture =   500
C_fixture =   0
L_fixture =   0
V_fixture =   0
V_fixture_min = 0
V_fixture_max = 0
|   Time   V(typ)   V(min)   V(max)
0s        495.2pV    1.396nV    369.6pV
1.95ns    -529.7uV   894.8uV    53.17mV
2.175ns   -3.508mV   1.301mV    516.9mV
2.445ns   147.4mV    -2.188mV   2.278V
2.605ns   394.1mV    -4.482mV   2.901V
3.045ns   2.236V     48.4mV     3.325V
3.35ns    2.799V     305.9mV    3.377V
4.16ns    3.04V      2.293V     3.393V
5.33ns    3.055V     2.696V     3.394V
50ns      3.055V     2.715V     3.394V
[Falling Waveform]
| ALVCH162601_IOB_33
R_fixture =   500
C_fixture =   0
L_fixture =   0
V_fixture =   3.3
V_fixture_min = 3
V_fixture_max = 3.6
|   Time   V(typ)   V(min)   V(max)
0s        3.3V       3V         3.6V
2.345ns   3.298V     2.999V     3.587V
2.515ns   3.307V     2.998V     3.04V
2.73ns    3.288V     2.999V     1.002V
2.935ns   2.784V     3.005V     411.2mV
3.25ns    861.2mV    3.02V      234.2mV
3.64ns    314mV      2.56V      176.1mV
4.195ns   217.1mV    596.5mV    163.7mV
5.275ns   190.7mV    240.5mV    162.3mV
50ns      189.7mV    214.5mV    162.1mV
[Rising Waveform]
| ALVCH162601_IOB_33
R_fixture =   500
C_fixture =   0
L_fixture =   0
V_fixture =   3.3
V_fixture_min = 3
V_fixture_max = 3.6
|   Time   V(typ)   V(min)   V(max)
0s        189.7mV    214.5mV    162.1mV
1.92ns    189.4mV    215.2mV    190.6mV
2.16ns    185.6mV    215.4mV    639.5mV
2.365ns   263.1mV    212.7mV    1.988V
2.66ns    766.1mV    208.9mV    3.237V
3.03ns    2.474V     262.5mV    3.536V
3.325ns   3.043V     523.5mV    3.583V
4.11ns    3.285V     2.567V     3.598V
5.22ns    3.299V     2.981V     3.6V
50ns      3.3V       3V         3.6V
[Falling Waveform]
| ALVCH162601_IOB_33
R_fixture =   500
C_fixture =   0
L_fixture =   0
V_fixture =   0
V_fixture_min = 0
V_fixture_max = 0
|   Time   V(typ)   V(min)   V(max)
0s        3.055V     2.715V     3.394V
2.345ns   3.054V     2.714V     3.38V
2.51ns    3.063V     2.713V     2.851V
2.725ns   3.045V     2.714V     839.1mV
2.915ns   2.599V     2.72V      274.6mV
3.24ns    642mV      2.732V     72.98mV
3.61ns    131mV      2.305V     13.9mV
4.17ns    24.7mV     367.3mV    1.531mV
5.285ns   796.7uV    20.2mV     183.1uV
50ns      923.9nV    1.373uV    544nV
